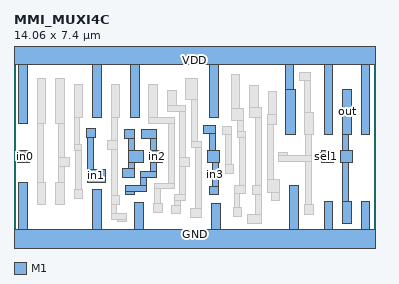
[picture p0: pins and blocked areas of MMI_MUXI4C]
MACRO MMI_MUXI4C
	CLASS CORE ;
	FOREIGN MMI_MUXI4C 0 0 ;
	SIZE 14.06 BY 7.4 ;
	SYMMETRY X Y ;
	SITE CORE1 ;
	PIN out
		DIRECTION output ;
		USE SIGNAL ;
		PORT
			LAYER M1 ;
			RECT 12.8 4.19 13.14 5.95 ;
			LAYER M1 ;
			RECT 12.8 3.555 13.03 4.19 ;
			LAYER M1 ;
			RECT 12.725 3.105 13.175 3.555 ;
			LAYER M1 ;
			RECT 12.8 1.57 13.03 3.105 ;
			LAYER M1 ;
			RECT 12.8 0.73 13.14 1.57 ;
		END
		AntennaDiffArea 1.4904 ;
	END out
	PIN sel0
		DIRECTION input ;
		USE SIGNAL ;
		PORT
			LAYER M1 ;
			RECT 4.305 4.05 4.685 4.39 ;
			LAYER M1 ;
			RECT 4.455 3.555 4.685 4.05 ;
			LAYER M1 ;
			RECT 4.455 3.105 5.035 3.555 ;
			LAYER M1 ;
			RECT 4.455 2.86 4.685 3.105 ;
			LAYER M1 ;
			RECT 4.245 2.52 4.685 2.86 ;
		END
		AntennaGateArea 1.4904 ;
	END sel0
	PIN in1
		DIRECTION input ;
		USE SIGNAL ;
		PORT
			LAYER M1 ;
			RECT 2.82 4.07 3.16 4.41 ;
			LAYER M1 ;
			RECT 2.87 2.83 3.1 4.07 ;
			LAYER M1 ;
			RECT 2.87 2.815 3.21 2.83 ;
			LAYER M1 ;
			RECT 2.87 2.335 3.555 2.815 ;
		END
		AntennaGateArea 0.4968 ;
	END in1
	PIN GND
		DIRECTION inout ;
		USE GROUND ;
		PORT
			LAYER M1 ;
			RECT 0.18 0.5 0.52 2.3 ;
			LAYER M1 ;
			RECT 3.06 0.5 3.4 2.04 ;
			LAYER M1 ;
			RECT 4.71 0.5 5.05 1.52 ;
			LAYER M1 ;
			RECT 7.7 0.5 8.04 1.515 ;
			LAYER M1 ;
			RECT 10.73 0.5 11.07 2.22 ;
			LAYER M1 ;
			RECT 12.08 0.5 12.42 1.57 ;
			LAYER M1 ;
			RECT 13.52 0.5 13.86 1.57 ;
			LAYER M1 ;
			RECT 0 -0.5 14.06 0.5 ;
		END
	END GND
	PIN sel1
		DIRECTION input ;
		USE SIGNAL ;
		PORT
			LAYER M1 ;
			RECT 11.985 3.5 12.435 3.555 ;
			LAYER M1 ;
			RECT 11.865 3.16 12.435 3.5 ;
			LAYER M1 ;
			RECT 11.985 3.105 12.435 3.16 ;
		END
		AntennaGateArea 0.7452 ;
	END sel1
	PIN in2
		DIRECTION input ;
		USE SIGNAL ;
		PORT
			LAYER M1 ;
			RECT 4.975 4.05 5.555 4.39 ;
			LAYER M1 ;
			RECT 5.325 3.555 5.555 4.05 ;
			LAYER M1 ;
			RECT 5.325 3.105 5.775 3.555 ;
			LAYER M1 ;
			RECT 5.325 2.755 5.555 3.105 ;
			LAYER M1 ;
			RECT 4.915 2.525 5.555 2.755 ;
			LAYER M1 ;
			RECT 4.915 2.19 5.145 2.525 ;
			LAYER M1 ;
			RECT 4.35 1.96 5.145 2.19 ;
			LAYER M1 ;
			RECT 4.35 1.85 4.69 1.96 ;
		END
		AntennaGateArea 0.4968 ;
	END in2
	PIN VDD
		DIRECTION inout ;
		USE POWER ;
		PORT
			LAYER M1 ;
			RECT 0 6.9 14.06 7.9 ;
			LAYER M1 ;
			RECT 0.18 4.6 0.52 6.9 ;
			LAYER M1 ;
			RECT 3.06 4.85 3.4 6.9 ;
			LAYER M1 ;
			RECT 4.535 4.85 4.875 6.9 ;
			LAYER M1 ;
			RECT 7.61 4.83 7.95 6.9 ;
			LAYER M1 ;
			RECT 10.56 5.935 10.9 6.9 ;
			LAYER M1 ;
			RECT 10.56 4.175 10.96 5.935 ;
			LAYER M1 ;
			RECT 12.08 4.19 12.42 6.9 ;
			LAYER M1 ;
			RECT 13.52 4.19 13.86 6.9 ;
		END
	END VDD
	PIN in3
		DIRECTION input ;
		USE SIGNAL ;
		PORT
			LAYER M1 ;
			RECT 7.385 4.215 7.86 4.555 ;
			LAYER M1 ;
			RECT 7.63 3.555 7.86 4.215 ;
			LAYER M1 ;
			RECT 7.545 3.105 7.995 3.555 ;
			LAYER M1 ;
			RECT 7.73 2.175 7.96 3.105 ;
			LAYER M1 ;
			RECT 7.62 1.835 7.96 2.175 ;
		END
		AntennaGateArea 0.4968 ;
	END in3
	PIN in0
		DIRECTION input ;
		USE SIGNAL ;
		PORT
			LAYER M1 ;
			RECT 0.145 3.505 0.595 3.555 ;
			LAYER M1 ;
			RECT 0.145 3.165 0.65 3.505 ;
			LAYER M1 ;
			RECT 0.145 3.105 0.595 3.165 ;
		END
		AntennaGateArea 0.4968 ;
	END in0
	OBS
		LAYER M1 ;
		RECT 0.9 4.6 1.24 6.36 ;
		LAYER M1 ;
		RECT 1.62 4.6 1.96 6.36 ;
		LAYER M1 ;
		RECT 0.9 2.3 1.13 4.6 ;
		LAYER M1 ;
		RECT 1.73 3.29 1.96 4.6 ;
		LAYER M1 ;
		RECT 2.34 4.85 2.68 6.13 ;
		LAYER M1 ;
		RECT 3.78 4.85 4.12 6.13 ;
		LAYER M1 ;
		RECT 6.695 6.355 7.035 6.36 ;
		LAYER M1 ;
		RECT 5.255 4.85 5.595 6.135 ;
		LAYER M1 ;
		RECT 5.975 5.315 6.315 5.905 ;
		LAYER M1 ;
		RECT 6.695 5.55 7.155 6.355 ;
		LAYER M1 ;
		RECT 5.975 5.085 6.695 5.315 ;
		LAYER M1 ;
		RECT 2.34 3.81 2.57 4.85 ;
		LAYER M1 ;
		RECT 2.34 3.58 2.62 3.81 ;
		LAYER M1 ;
		RECT 1.73 2.95 2.15 3.29 ;
		LAYER M1 ;
		RECT 1.73 2.3 1.96 2.95 ;
		LAYER M1 ;
		RECT 0.9 1.46 1.24 2.3 ;
		LAYER M1 ;
		RECT 1.62 1.46 1.96 2.3 ;
		LAYER M1 ;
		RECT 2.39 2.04 2.62 3.58 ;
		LAYER M1 ;
		RECT 3.785 3.96 4.015 4.85 ;
		LAYER M1 ;
		RECT 5.255 4.62 6.235 4.85 ;
		LAYER M1 ;
		RECT 3.635 3.62 4.015 3.96 ;
		LAYER M1 ;
		RECT 2.34 1.7 2.68 2.04 ;
		LAYER M1 ;
		RECT 3.785 1.8 4.015 3.62 ;
		LAYER M1 ;
		RECT 6.005 2.295 6.235 4.62 ;
		LAYER M1 ;
		RECT 5.475 2.065 6.235 2.295 ;
		LAYER M1 ;
		RECT 6.465 3.29 6.695 5.085 ;
		LAYER M1 ;
		RECT 6.925 3.925 7.155 5.55 ;
		LAYER M1 ;
		RECT 8.46 5.19 8.8 6.505 ;
		LAYER M1 ;
		RECT 9.18 5.245 9.52 6.11 ;
		LAYER M1 ;
		RECT 11.13 6.275 11.55 6.615 ;
		LAYER M1 ;
		RECT 8.46 4.745 8.95 5.19 ;
		LAYER M1 ;
		RECT 9.18 4.83 9.63 5.245 ;
		LAYER M1 ;
		RECT 9.9 4.965 10.24 5.855 ;
		LAYER M1 ;
		RECT 6.925 3.695 7.31 3.925 ;
		LAYER M1 ;
		RECT 6.465 2.95 6.85 3.29 ;
		LAYER M1 ;
		RECT 3.78 1.46 4.12 1.8 ;
		LAYER M1 ;
		RECT 3.78 1.125 4.01 1.46 ;
		LAYER M1 ;
		RECT 3.78 0.895 4.39 1.125 ;
		LAYER M1 ;
		RECT 4.05 0.785 4.39 0.895 ;
		LAYER M1 ;
		RECT 5.475 1.495 5.705 2.065 ;
		LAYER M1 ;
		RECT 6.465 1.835 6.695 2.95 ;
		LAYER M1 ;
		RECT 6.26 1.605 6.695 1.835 ;
		LAYER M1 ;
		RECT 5.43 1.155 5.77 1.495 ;
		LAYER M1 ;
		RECT 6.26 1.44 6.49 1.605 ;
		LAYER M1 ;
		RECT 6.15 1.1 6.49 1.44 ;
		LAYER M1 ;
		RECT 7.08 1.295 7.31 3.695 ;
		LAYER M1 ;
		RECT 8.13 4.17 8.47 4.51 ;
		LAYER M1 ;
		RECT 8.24 3.02 8.47 4.17 ;
		LAYER M1 ;
		RECT 8.72 4.305 8.95 4.745 ;
		LAYER M1 ;
		RECT 8.72 4.06 9.025 4.305 ;
		LAYER M1 ;
		RECT 8.225 2.68 8.565 3.02 ;
		LAYER M1 ;
		RECT 8.795 2.215 9.025 4.06 ;
		LAYER M1 ;
		RECT 8.57 1.875 9.025 2.215 ;
		LAYER M1 ;
		RECT 9.4 2.2 9.63 4.83 ;
		LAYER M1 ;
		RECT 6.87 0.955 7.31 1.295 ;
		LAYER M1 ;
		RECT 8.57 1.33 8.8 1.875 ;
		LAYER M1 ;
		RECT 9.29 1.86 9.63 2.2 ;
		LAYER M1 ;
		RECT 9.86 4.575 10.24 4.965 ;
		LAYER M1 ;
		RECT 9.86 2.45 10.09 4.575 ;
		LAYER M1 ;
		RECT 11.32 5.03 11.55 6.275 ;
		LAYER M1 ;
		RECT 11.32 4.19 11.66 5.03 ;
		LAYER M1 ;
		RECT 10.32 3.37 10.66 3.48 ;
		LAYER M1 ;
		RECT 11.34 3.37 11.57 4.19 ;
		LAYER M1 ;
		RECT 10.32 3.14 11.57 3.37 ;
		LAYER M1 ;
		RECT 9.86 1.91 10.35 2.45 ;
		LAYER M1 ;
		RECT 8.53 0.99 8.87 1.33 ;
		LAYER M1 ;
		RECT 9.4 1.07 9.63 1.86 ;
		LAYER M1 ;
		RECT 10.01 1.61 10.35 1.91 ;
		LAYER M1 ;
		RECT 9.1 0.73 9.63 1.07 ;
		LAYER M1 ;
		RECT 11.34 1.45 11.57 3.14 ;
		LAYER M1 ;
		RECT 11.32 1.07 11.66 1.45 ;
	END
END MMI_MUXI4C
